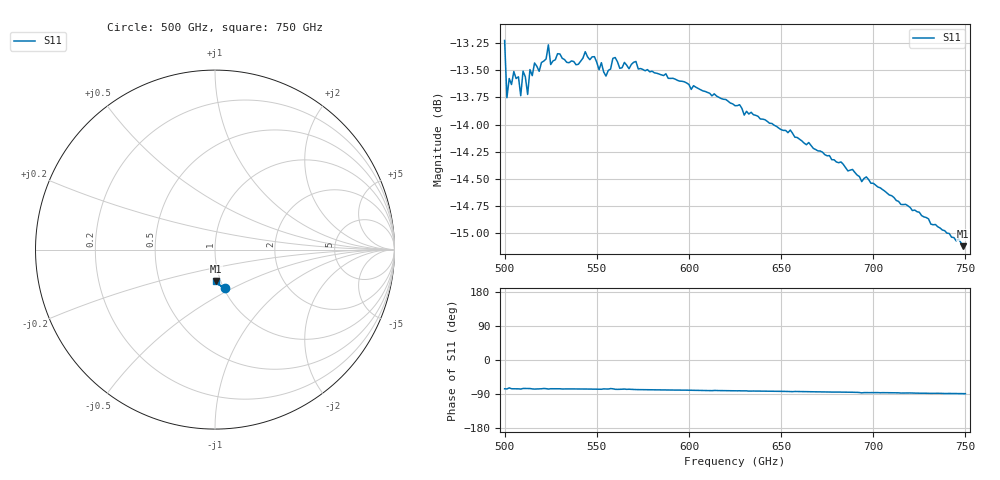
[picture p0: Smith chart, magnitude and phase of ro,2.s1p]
!Created with mwavepy.
! Created with skrf 2.0.1 (http://scikit-rf.org).
# GHz S RI R 50.0
!freq ReS11 ImS11
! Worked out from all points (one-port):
!   201 points, 500 GHz to 750 GHz, reference 50 ohm
!   lowest |S11| = -15.1 dB at 748.8 GHz (marker M1), VSWR 1.43, Z = 47.3 - j17.1 ohm
!   |S11| at or under -10 dB: start of sweep to end of sweep
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500  0.0531 -0.2115
501.25  0.0484 -0.1995
502.5  0.0592 -0.2009
503.75  0.0508 -0.2019
505  0.051 -0.2048
507.5  0.0504 -0.2037
508.75  0.0473 -0.2002
510  0.0543 -0.204
512.5  0.052 -0.1993
513.75  0.0536 -0.2045
518.75  0.0507 -0.2049
523.75  0.0501 -0.2112
525  0.052 -0.2061
531.25  0.0501 -0.2081
540  0.0511 -0.2064
543.75  0.0503 -0.2095
551.25  0.0468 -0.2062
557.5  0.0533 -0.2048
560  0.0471 -0.2089
562.5  0.0466 -0.2066
571.25  0.0441 -0.2087
593.75  0.0387 -0.2055
625  0.0312 -0.2011
656.25  0.0224 -0.1964
687.5  0.0167 -0.1894
718.75  0.00923 -0.1829
748.75  0.00359 -0.1754
750  0.00353 -0.1757
